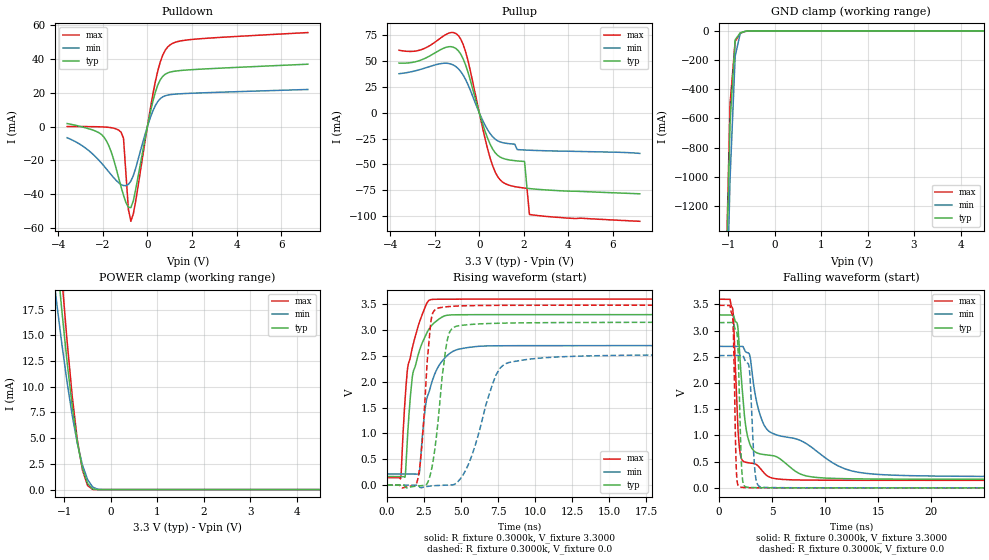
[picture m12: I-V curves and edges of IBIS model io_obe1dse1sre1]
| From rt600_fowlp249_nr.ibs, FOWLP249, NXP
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[Model] io_obe1dse1sre1
|   Model io_obe1dse1sre1
| Library cells for typ/min/max conditions are connected as defined below:
|  pad - External Pad
|  ipp_do - Core Input
|  ipp_obe - Output Buffer Enable
|  REFH3V3 - vdd1v8
|  REFL3V3 - REFL3V3
|  gnde - gnde
|  ipp_dse - vdd
|  ipp_ina235_3v - NC
|  ipp_ina40_3v - NC
|  ipp_ina_mux - NC
|  ipp_ind - NC
|  ipp_ind_1p8v - NC
|  ipp_ind_3v - NC
|  ipp_sre - vdd
|  vdd - vdd
|  vdd1v8 - vdd1v8
|  vdda - vdde3v3
|  vdde3v3 - vdde3v3
| All other pins connected to ground
Model_type I/O
Polarity   Non-Inverting
Enable   Active-High
Vinl =   0.9900V
Vinh =   2.3100V
Vmeas =  1.6500V
Cref =   25.0000pF
Rref =   0.5000k
Vref =   0.0V
C_comp   1.8909pF   1.8218pF   2.0890pF
[Temperature Range]   25.0000   0.1250k   -40.0000
[Voltage Range]   3.3000V   2.7000V   3.6000V
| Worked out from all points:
|   slope of the pulldown table from 0 to 0.495 V, typ, clamps not added: 19.4 ohm
|   slope of the pullup table from 0 to 0.495 V, typ, clamps not added: 16 ohm
|   GND clamp passes 1 mA (typ) near -0.55 V on its own axis
|   POWER clamp passes 1 mA (typ) near -0.53 V on its own axis
|   rising waveform, R_fixture 0.3000k, V_fixture 3.3000: 20-80 % time 917ps typ, 985ps min, 884ps max; typ from 0.165 V to 3.3 V
|   rising waveform, R_fixture 0.3000k, V_fixture 0.0: 20-80 % time 715ps typ, 1.57ns min, 494ps max; typ from 0 V to 3.15 V
|   falling waveform, R_fixture 0.3000k, V_fixture 3.3000: 20-80 % time 1.08ns typ, 6ns min, 461ps max; typ from 3.3 V to 0.165 V
|   falling waveform, R_fixture 0.3000k, V_fixture 0.0: 20-80 % time 264ps typ, 365ps min, 203ps max; typ from 3.15 V to 0 V
[Pulldown]
|Voltage   I(typ)   I(min)   I(max)
-3.6V     1.86mA     -6.52mA    100uA
-1.95V    -6.13mA    -23.21mA   -180uA
-1.62V    -14.97mA   -28.49mA   -590uA
-1.18V    -35.64mA   -34.24mA   -3.216mA
-1.07V    -40.67mA   -34.88mA   -6.929mA
-850mV    -47.74mA   -34.14mA   -49.09mA
-740mV    -47.9mA    -32.2mA    -56.02mA
-520mV    -36.89mA   -24.41mA   -43.8mA
360mV     20.57mA    12.57mA    26.82mA
580mV     27.83mA    16.63mA    38.42mA
910mV     31.85mA    18.72mA    47.2mA
7.2V      37.02mA    22.05mA    55.76mA
[Pullup]
|Voltage   I(typ)   I(min)   I(max)
-3.6V     48.16mA    37.9mA     60.62mA
-2.59V    51.35mA    42.34mA    61.31mA
-1.6V     62.63mA    48.02mA    74.55mA
-940mV    60.15mA    42.71mA    74.92mA
-500mV    38.89mA    26.95mA    50.05mA
160mV     -11.43mA   -7.699mA   -15.76mA
600mV     -35.24mA   -23.3mA    -51.47mA
1.04V     -44.06mA   -28.96mA   -67.12mA
2.03V     -47.27mA   -36.13mA   -73.08mA
2.14V     -73.27mA   -36.24mA   -73.35mA
2.25V     -73.54mA   -36.34mA   -98.66mA
7.2V      -78.63mA   -39.43mA   -105.3mA
[GND_clamp]
|Voltage   I(typ)   I(min)   I(max)
-3.6V     -46.64A    -46.27A    -48.09A
-1.07V    -2.038A    -2.424A    -1.965A
-960mV    -629.9mA   -1.012A    -499.2mA
-850mV    -61.62mA   -174.1mA   -72.03mA
-740mV    -13.6mA    -15.68mA   -16.3mA
-630mV    -2.659mA   -3.244mA   -3.911mA
-410mV    -9.214uA   -49.17uA   -3.123uA
7.2V      0A         0A         0A
[POWER_clamp]
|Voltage   I(typ)   I(min)   I(max)
-3.6V     124.7mA    103.4mA    137.3mA
-1.27V    28.14mA    22.17mA    33.67mA
-1.16V    22.5mA     17.97mA    26.85mA
-1.05V    17.19mA    14.01mA    20.36mA
-940mV    12.34mA    10.39mA    14.37mA
-830mV    8.067mA    7.189mA    9.044mA
-720mV    4.554mA    4.475mA    4.783mA
-610mV    2.051mA    2.374mA    1.895mA
-500mV    596.8uA    974uA      390.7uA
-390mV    63.25uA    246uA      14.24uA
-170mV    55.4nA     1.772uA    16.57nA
7.2V      0A         0A         0A
[Ramp]
| variable   typ   min   max
dV/dt_r  1.3314/1.2964n   0.8903/3.3108n   1.7299/0.9589n
dV/dt_f  1.0033/7.8375n   0.5900/11.4877n   1.4811/4.7671n
R_load = 50.0000
[Rising Waveform]
R_fixture= 0.3000k
V_fixture= 3.3000
V_fixture_min= 2.7000
V_fixture_max= 3.6000
|time   V(typ)   V(min)   V(max)
0s        164.8mV    215.1mV    143.9mV
923.2ps   164.8mV    215.1mV    132.6mV
1.218ns   159.5mV    215.1mV    1.642V
1.682ns   2.023V     215.1mV    2.619V
2.167ns   2.581V     212.5mV    3.133V
2.629ns   2.912V     1.581V     3.482V
3.191ns   3.141V     2.124V     3.597V
4.595ns   3.297V     2.607V     3.599V
8.367ns   3.3V       2.698V     3.6V
500ns     3.3V       2.7V       3.6V
[Rising Waveform]
R_fixture= 0.3000k
V_fixture= 0.0
V_fixture_min= 0.0
V_fixture_max= 0.0
|time   V(typ)   V(min)   V(max)
0s        31.94nV    709.3nV    82.55nV
2.014ns   -19.04mV   60.82uV    45.4mV
2.357ns   -11.5mV    -49.52mV   758.8mV
2.746ns   48.58mV    -25.78mV   2.48V
3.088ns   419.7mV    -14.36mV   3.327V
4.122ns   2.865V     -2.091mV   3.455V
5.351ns   3.101V     307.1mV    3.472V
7.935ns   3.136V     2.341V     3.48V
15.08ns   3.15V      2.509V     3.483V
500ns     3.153V     2.524V     3.483V
[Falling Waveform]
R_fixture= 0.3000k
V_fixture= 3.3000
V_fixture_min= 2.7000
V_fixture_max= 3.6000
|time   V(typ)   V(min)   V(max)
0s        3.3V       2.7V       3.6V
1.306ns   3.3V       2.7V       3.402V
1.796ns   3.041V     2.7V       1.119V
2.118ns   2.077V     2.7V       558.8mV
3.035ns   778.1mV    2.359V     473.3mV
4.251ns   634.9mV    1.2V       284mV
6.555ns   419.5mV    963.1mV    155.3mV
12.46ns   172.8mV    324.9mV    144.5mV
22.02ns   165.2mV    222mV      143.9mV
500ns     164.8mV    215.1mV    143.9mV
[Falling Waveform]
R_fixture= 0.3000k
V_fixture= 0.0
V_fixture_min= 0.0
V_fixture_max= 0.0
|time   V(typ)   V(min)   V(max)
0s        3.153V     2.524V     3.483V
1.287ns   3.153V     2.524V     3.272V
1.598ns   3.005V     2.524V     600mV
1.699ns   2.96V      2.524V     154.4mV
2.156ns   318.9mV    2.525V     10.09mV
2.586ns   14.91mV    2.396V     4.266mV
2.911ns   7.857mV    2.164V     2.591mV
3.477ns   4.106mV    179.9mV    1.327mV
4.713ns   1.532mV    6.25mV     532.3uV
500ns     395.9nV    1.162uV    302.2nV
